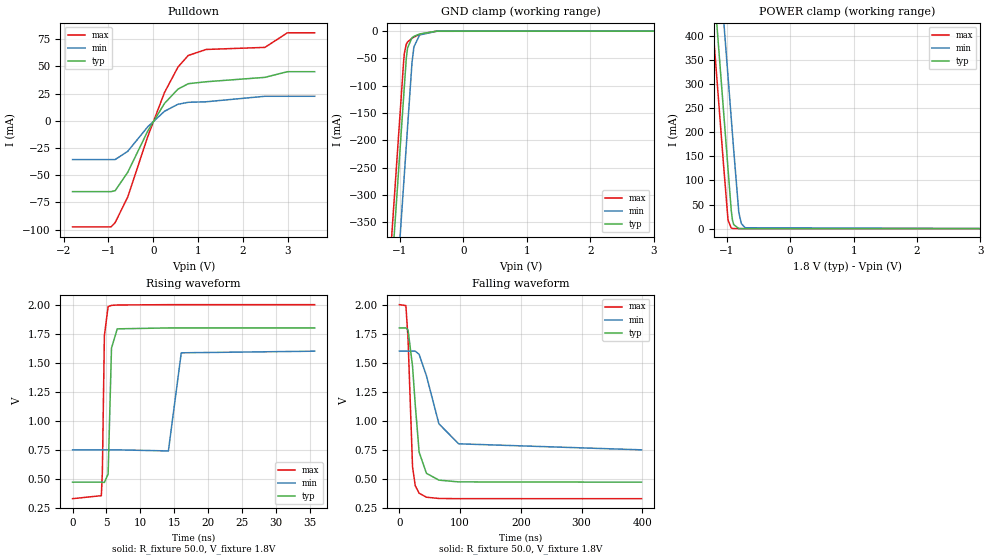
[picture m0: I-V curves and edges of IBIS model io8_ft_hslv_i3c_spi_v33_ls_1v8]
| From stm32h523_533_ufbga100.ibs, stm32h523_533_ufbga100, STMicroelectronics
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[Model]   io8_ft_hslv_i3c_spi_v33_ls_1v8
Model_type I/O_open_drain
Polarity   Non-Inverting
Enable   Active-Low
| CAP_THRESHOLD on pad IOFT is "UDTCAPC" :
| Rising=20.0% of vddiom   Falling=80.0% of vddiom
| C_comp min and max val. don't necessarily correlate with the min and max pvt
| but are the smallest and greatest pad capacitance found.
| var   typ   min   max
C_comp   3.69208pF  3.66970pF  3.86726pF
|C_comp_pulldown   3.69208pF  3.66970pF  3.86726pF
Vinl = 800.0mV
Vinh = 1.0V
Vmeas = 900.0mV   | Reference voltage for timing measurements
Cref  = 50.0pF   | Timing specification test load capacitance value
Rref  = 1.0MOhm   | Timing specification test load resistance value
Vref  = 990.0mV   | Timing specification test load voltage
[Model Spec]
| TIME_THRESHOLD on pin ZII2CV11 is "CMOS" :
| Rising=40.0% of vdd   Falling=60.0% of vdd
Vinl 693.80000mV 621.80000mV 774.80000mV
Vinh 1.05820V 933.20000mV 1.16320V
| variable   typ   min   max
[Temperature Range] 25.0 125.0 -40.0
| variable   typ   min   max
[Voltage Range] 1.8V 1.6V 2.0V
| variable   typ   min   max
[POWER Clamp Reference] 1.8V 1.6V 2.0V
| variable   typ   min   max
[GND Clamp Reference] 0V 0V 0V
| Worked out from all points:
|   slope of the pulldown table from 0 to 0.27 V, typ, clamps not added: 15.8 ohm
|   GND clamp passes 1 mA (typ) near -0.52 V on its own axis
|   POWER clamp passes 1 mA (typ) near -0.84 V on its own axis
|   rising waveform, R_fixture 50.0, V_fixture 1.8V: 20-80 % time 286ps typ, 466ps min, 243ps max; typ from 0.474 V to 1.8 V
|   falling waveform, R_fixture 50.0, V_fixture 1.8V: 20-80 % time 11.7ns typ, 28.5ns min, 6.6ns max; typ from 1.8 V to 0.474 V
[POWER Clamp]
-1.8V     1.518A     1.709A     1.407A
-1.23V    548.8mA    740.2mA    437.5mA
-1.16V    429.8mA    621.2mA    318.5mA
-1.05V    242.8mA    434.2mA    131.5mA
-980mV    123.8mA    315.2mA    17.95mA
-930mV    38.81mA    230.2mA    1.49mA
-910mV    17.82mA    196.2mA    550.8uA
-890mV    8.18mA     162.2mA    203.5uA
-810mV    363.5uA    33.6mA     3.797uA
-770mV    76.62uA    10.47mA    518.8nA
-710mV    7.416uA    1.822mA    26.33nA
3.6V      0A         0A         0A
[GND Clamp]
-1.8V     -1.579A    -1.74A     -1.515A
-1.24V    -627.3mA   -788.3mA   -562.7mA
-1.05V    -304.3mA   -465.3mA   -239.7mA
-940mV    -117.3mA   -278.3mA   -52.69mA
-930mV    -100.3mA   -261.3mA   -40.52mA
-900mV    -50.11mA   -210.3mA   -24.23mA
-880mV    -30.95mA   -176.3mA   -20.02mA
-810mV    -12.18mA   -57.97mA   -13.23mA
-780mV    -9.807mA   -29.1mA    -11.19mA
-690mV    -5.41mA    -7.142mA   -6.184mA
-420mV    -170.4uA   -446.1uA   -81.94uA
3.6V      5.755nA    953.2nA    228.2pA
| variable   typ   min   max
[Pullup Reference] 1.8V 1.6V 2.0V
| variable   typ   min   max
[Pulldown Reference] 0V 0V 0V
[Pulldown]
-1.8V     -65.02mA   -35.56mA   -97.42mA
-940mV    -65.02mA   -35.56mA   -97.42mA
-850mV    -64.17mA   -35.56mA   -93.49mA
-570mV    -47.32mA   -28.01mA   -70.04mA
-120mV    -9.088mA   -5.279mA   -14.07mA
250mV     16.04mA    8.832mA    26.05mA
550mV     29.17mA    15.25mA    49.41mA
780mV     34.17mA    17.07mA    60.14mA
1.18V     35.97mA    17.56mA    65.65mA
2.49V     40mA       22.62mA    67.56mA
2.99V     45.21mA    22.62mA    80.94mA
3.6V      45.21mA    22.62mA    80.94mA
[Ramp]
dV/dt_r 795.76282mV/283.06948ps 508.89047mV/465.17552ps 1.00097V/238.84657ps
dV/dt_f 795.7871mV/11.67095ns 508.95874mV/28.08898ns 1.00099V/6.47057ns
R_load = 50.0
| Removed startup time: 0s 0s 0s  .
| Removed end time: 35.75ns.
[Rising Waveform]
R_fixture   = 50.0
V_fixture   = 1.8V
V_fixture_min = 1.6V
V_fixture_max = 2.0V
0s        473.7mV    751.7mV    331.7mV
4.25ns    473.7mV    751.7mV    357.7mV
4.4ns     473.4mV    751.7mV    558.5mV
4.7ns     471mV      751.7mV    1.734V
5.25ns    543.7mV    751.7mV    1.984V
5.75ns    1.627V     751.7mV    1.994V
6.6ns     1.792V     751.7mV    1.997V
14.15ns   1.8V       742.2mV    2V
16.05ns   1.8V       1.586V     2V
35.75ns   1.8V       1.6V       2V
| Removed startup time: 0s 0s 0s  .
| Removed end time: 398.75ns.
[Falling Waveform]
R_fixture   = 50.0
V_fixture   = 1.8V
V_fixture_min = 1.6V
V_fixture_max = 2.0V
0s        1.8V       1.6V       2V
10.75ns   1.8V       1.6V       1.992V
14.25ns   1.783V     1.6V       1.71V
21.7ns    1.47V      1.6V       605.4mV
26.2ns    1.136V     1.6V       442.7mV
32.55ns   731.7mV    1.573V     378.8mV
44.6ns    550mV      1.388V     344.3mV
65.1ns    491.4mV    975.6mV    333.5mV
97.65ns   476mV      803.5mV    331.8mV
398.8ns   473.7mV    751.7mV    331.7mV
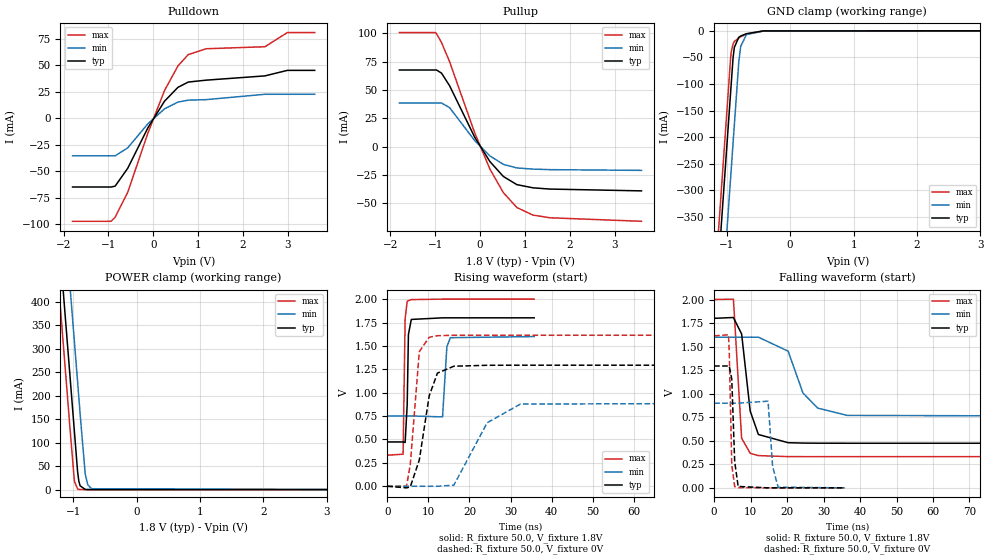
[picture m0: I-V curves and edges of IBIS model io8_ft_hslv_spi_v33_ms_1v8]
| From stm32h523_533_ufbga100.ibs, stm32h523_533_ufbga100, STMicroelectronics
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[Model]   io8_ft_hslv_spi_v33_ms_1v8
Model_type I/O
Polarity   Non-Inverting
Enable   Active-Low
| CAP_THRESHOLD on pad IOFT is "UDTCAPC" :
| Rising=20.0% of vddiom   Falling=80.0% of vddiom
| C_comp min and max val. don't necessarily correlate with the min and max pvt
| but are the smallest and greatest pad capacitance found.
| var   typ   min   max
C_comp   3.69213pF  3.66975pF  3.86731pF
|C_comp_pullup   2.29915pF  2.22620pF  2.22545pF
|C_comp_pulldown   1.39298pF  1.44355pF  1.64186pF
Vinl = 480.0mV
Vinh = 1.4V
Vmeas = 900.0mV   | Reference voltage for timing measurements
Cref  = 50.0pF   | Timing specification test load capacitance value
Rref  = 100.0MOhm   | Timing specification test load resistance value
Vref  = 900.0mV   | Timing specification test load voltage
[Model Spec]
| TIME_THRESHOLD on pin ZIV33M is "CMOS" :
| Rising=40.0% of vddiom   Falling=60.0% of vddiom
Vinl 693.80000mV 621.80000mV 774.80000mV
Vinh 1.05820V 933.20000mV 1.16320V
| variable   typ   min   max
[Temperature Range] 25.0 125.0 -40.0
| variable   typ   min   max
[Voltage Range] 1.8V 1.6V 2.0V
| variable   typ   min   max
[POWER Clamp Reference] 1.8V 1.6V 2.0V
| variable   typ   min   max
[GND Clamp Reference] 0V 0V 0V
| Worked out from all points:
|   slope of the pulldown table from 0 to 0.27 V, typ, clamps not added: 15.8 ohm
|   slope of the pullup table from 0 to 0.27 V, typ, clamps not added: 17.1 ohm
|   GND clamp passes 1 mA (typ) near -0.52 V on its own axis
|   POWER clamp passes 1 mA (typ) near -0.84 V on its own axis
|   rising waveform, R_fixture 50.0, V_fixture 1.8V: 20-80 % time 283ps typ, 446ps min, 243ps max; typ from 0.474 V to 1.8 V
|   falling waveform, R_fixture 50.0, V_fixture 1.8V: 20-80 % time 2.69ns typ, 5.8ns min, 1.28ns max; typ from 1.8 V to 0.474 V
|   rising waveform, R_fixture 50.0, V_fixture 0V: 20-80 % time 3.05ns typ, 6.53ns min, 1.58ns max; typ from 0 V to 1.29 V
|   falling waveform, R_fixture 50.0, V_fixture 0V: 20-80 % time 741ps typ, 1.07ns min, 549ps max; typ from 1.29 V to 0 V
[POWER Clamp]
-1.8V     1.518A     1.709A     1.407A
-1.23V    548.8mA    740.2mA    437.5mA
-1.16V    429.8mA    621.2mA    318.5mA
-1.05V    242.8mA    434.2mA    131.5mA
-980mV    123.8mA    315.2mA    17.95mA
-930mV    38.81mA    230.2mA    1.49mA
-910mV    17.82mA    196.2mA    550.8uA
-890mV    8.18mA     162.2mA    203.5uA
-810mV    363.5uA    33.6mA     3.797uA
-770mV    76.62uA    10.47mA    518.8nA
-710mV    7.416uA    1.822mA    26.33nA
3.6V      0A         0A         0A
[GND Clamp]
-1.8V     -1.579A    -1.74A     -1.515A
-1.24V    -627.3mA   -788.3mA   -562.7mA
-1.05V    -304.3mA   -465.3mA   -239.7mA
-940mV    -117.3mA   -278.3mA   -52.69mA
-930mV    -100.3mA   -261.3mA   -40.52mA
-900mV    -50.11mA   -210.3mA   -24.23mA
-880mV    -30.95mA   -176.3mA   -20.02mA
-810mV    -12.18mA   -57.97mA   -13.23mA
-780mV    -9.807mA   -29.1mA    -11.19mA
-690mV    -5.41mA    -7.142mA   -6.184mA
-420mV    -170.4uA   -446.1uA   -81.94uA
3.6V      5.755nA    953.2nA    228.2pA
| variable   typ   min   max
[Pullup Reference] 1.8V 1.6V 2.0V
| variable   typ   min   max
[Pulldown Reference] 0V 0V 0V
[Pullup]
-1.8V     67.74mA    38.62mA    100.8mA
-990mV    67.74mA    38.62mA    100.8mA
-970mV    67.74mA    38.62mA    99.7mA
-860mV    64.94mA    38.62mA    92.02mA
-680mV    53.84mA    34.48mA    75.07mA
-120mV    8.372mA    5.391mA    12.2mA
220mV     -13.2mA    -8.17mA    -19.85mA
520mV     -26.34mA   -15.62mA   -40.64mA
820mV     -33.51mA   -18.79mA   -53.71mA
1.18V     -36.34mA   -19.79mA   -60.45mA
1.56V     -37.44mA   -20.28mA   -62.79mA
3.6V      -39.03mA   -20.93mA   -65.9mA
[Pulldown]
-1.8V     -65.02mA   -35.56mA   -97.42mA
-940mV    -65.02mA   -35.56mA   -97.42mA
-850mV    -64.17mA   -35.56mA   -93.49mA
-570mV    -47.32mA   -28.01mA   -70.04mA
-120mV    -9.088mA   -5.279mA   -14.07mA
250mV     16.04mA    8.832mA    26.05mA
550mV     29.17mA    15.25mA    49.41mA
780mV     34.17mA    17.07mA    60.14mA
1.18V     35.97mA    17.56mA    65.65mA
2.49V     40mA       22.62mA    67.56mA
2.99V     45.21mA    22.62mA    80.94mA
3.6V      45.21mA    22.62mA    80.94mA
[Ramp]
dV/dt_r 776.16021mV/2.81986ns 539.54372mV/5.93573ns 968.53214mV/1.58093ns
dV/dt_f 795.78718mV/2.31042ns 508.97887mV/5.43453ns 1.00099V/1.27453ns
R_load = 50.0
| Removed startup time: 0s 0s 0s  .
| Removed end time: 35.75ns.
[Rising Waveform]
R_fixture   = 50.0
V_fixture   = 1.8V
V_fixture_min = 1.6V
V_fixture_max = 2.0V
0s        473.7mV    751.7mV    331.7mV
3.85ns    473.7mV    751.7mV    343.1mV
4.35ns    468mV      751.7mV    1.793V
4.85ns    872.5mV    751.7mV    1.975V
5.15ns    1.623V     751.7mV    1.984V
5.85ns    1.783V     751.7mV    1.995V
13.45ns   1.8V       741.4mV    2V
14.5ns    1.8V       1.491V     2V
15.35ns   1.8V       1.588V     2V
35.75ns   1.8V       1.6V       2V
| Removed startup time: 0s 0s 0s  .
| Removed end time: 198.75ns.
[Falling Waveform]
R_fixture   = 50.0
V_fixture   = 1.8V
V_fixture_min = 1.6V
V_fixture_max = 2.0V
0s        1.8V       1.6V       2V
5.3ns     1.809V     1.6V       2.004V
7.55ns    1.634V     1.6V       527.7mV
9.9ns     815.4mV    1.6V       366.5mV
12.15ns   566.5mV    1.6V       342.4mV
20.3ns    479.4mV    1.451V     331.9mV
24.35ns   475.4mV    1.008V     331.7mV
28.4ns    474.2mV    846.5mV    331.7mV
36.5ns    473.7mV    769.4mV    331.7mV
198.8ns   473.7mV    751.7mV    331.7mV
| Removed startup time: 0s 0s 0s  .
| Removed end time: 198.6ns.
[Rising Waveform]
R_fixture   = 50.0
V_fixture   = 0V
V_fixture_min = 0V
V_fixture_max = 0V
0s        166.5nV    437.2nV    122.3nV
4.7ns     -16.92mV   436.2nV    2.707mV
5.6ns     -6.732mV   418.8nV    234.6mV
7.8ns     281.8mV    331.7nV    1.439V
10.2ns    966mV      276.9nV    1.593V
12.2ns    1.209V     -1.233uV   1.609V
16.2ns    1.283V     11.66mV    1.614V
24.3ns    1.293V     678.8mV    1.614V
32.4ns    1.294V     878.5mV    1.614V
198.6ns   1.294V     899.2mV    1.614V
| Removed startup time: 0s 0s 0s  .
| Removed end time: 35.75ns.
[Falling Waveform]
R_fixture   = 50.0
V_fixture   = 0V
V_fixture_min = 0V
V_fixture_max = 0V
0s        1.294V     899.3mV    1.614V
3.95ns    1.294V     899.3mV    1.625V
4.15ns    1.294V     899.3mV    1.456V
4.85ns    1.155V     899.3mV    244.7mV
5.65ns    279.2mV    899.3mV    13.44mV
6.6ns     15.13mV    899.3mV    2.65mV
14.8ns    254.8uV    920.3mV    61.54uV
16.05ns   174.2uV    226.4mV    35.69uV
17.55ns   110.4uV    7.635mV    18.51uV
35.75ns   487.3nV    153.4uV    38.2nV
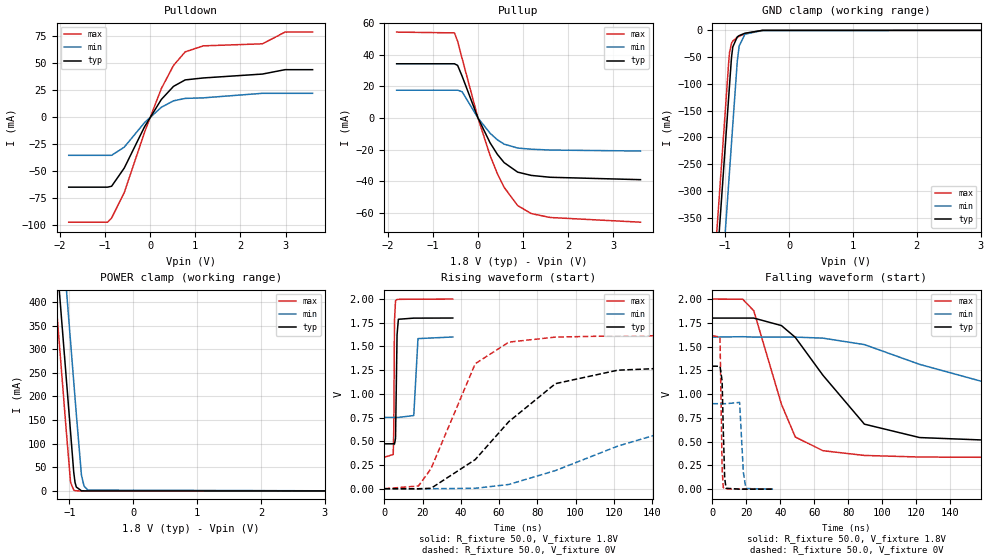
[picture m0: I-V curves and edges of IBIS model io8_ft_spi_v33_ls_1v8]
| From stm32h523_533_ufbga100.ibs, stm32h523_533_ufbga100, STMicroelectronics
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[Model]   io8_ft_spi_v33_ls_1v8
Model_type I/O
Polarity   Non-Inverting
Enable   Active-Low
| CAP_THRESHOLD on pad IOFT is "UDTCAPC" :
| Rising=20.0% of vddiom   Falling=80.0% of vddiom
| C_comp min and max val. don't necessarily correlate with the min and max pvt
| but are the smallest and greatest pad capacitance found.
| var   typ   min   max
C_comp   3.69193pF  3.66950pF  3.86716pF
|C_comp_pullup   2.28995pF  2.21765pF  2.21560pF
|C_comp_pulldown   1.40198pF  1.45185pF  1.65156pF
Vinl = 480.0mV
Vinh = 1.4V
Vmeas = 900.0mV   | Reference voltage for timing measurements
Cref  = 50.0pF   | Timing specification test load capacitance value
Rref  = 100.0MOhm   | Timing specification test load resistance value
Vref  = 900.0mV   | Timing specification test load voltage
[Model Spec]
| TIME_THRESHOLD on pin ZIV33M is "CMOS" :
| Rising=40.0% of vddiom   Falling=60.0% of vddiom
Vinl 693.80000mV 621.80000mV 774.80000mV
Vinh 1.05820V 933.20000mV 1.16320V
| variable   typ   min   max
[Temperature Range] 25.0 125.0 -40.0
| variable   typ   min   max
[Voltage Range] 1.8V 1.6V 2.0V
| variable   typ   min   max
[POWER Clamp Reference] 1.8V 1.6V 2.0V
| variable   typ   min   max
[GND Clamp Reference] 0V 0V 0V
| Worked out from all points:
|   slope of the pulldown table from 0 to 0.27 V, typ, clamps not added: 15.8 ohm
|   slope of the pullup table from 0 to 0.27 V, typ, clamps not added: 17.1 ohm
|   GND clamp passes 1 mA (typ) near -0.52 V on its own axis
|   POWER clamp passes 1 mA (typ) near -0.84 V on its own axis
|   rising waveform, R_fixture 50.0, V_fixture 1.8V: 20-80 % time 411ps typ, 846ps min, 288ps max; typ from 0.474 V to 1.8 V
|   falling waveform, R_fixture 50.0, V_fixture 1.8V: 20-80 % time 33.4ns typ, 83.1ns min, 17.2ns max; typ from 1.8 V to 0.474 V
|   rising waveform, R_fixture 50.0, V_fixture 0V: 20-80 % time 38.4ns typ, 81.5ns min, 20.1ns max; typ from 0 V to 1.29 V
|   falling waveform, R_fixture 50.0, V_fixture 0V: 20-80 % time 1.11ns typ, 1.59ns min, 753ps max; typ from 1.29 V to 0 V
[POWER Clamp]
-1.8V     1.518A     1.709A     1.407A
-1.23V    548.8mA    740.2mA    437.5mA
-1.16V    429.8mA    621.2mA    318.5mA
-1.05V    242.8mA    434.2mA    131.5mA
-980mV    123.8mA    315.2mA    17.95mA
-930mV    38.81mA    230.2mA    1.49mA
-910mV    17.82mA    196.2mA    550.8uA
-890mV    8.18mA     162.2mA    203.5uA
-810mV    363.5uA    33.6mA     3.797uA
-770mV    76.62uA    10.47mA    518.8nA
-710mV    7.416uA    1.822mA    26.34nA
3.6V      0A         0A         0A
[GND Clamp]
-1.8V     -1.579A    -1.74A     -1.515A
-1.24V    -627.3mA   -788.3mA   -562.7mA
-1.05V    -304.3mA   -465.3mA   -239.7mA
-940mV    -117.3mA   -278.3mA   -52.69mA
-930mV    -100.3mA   -261.3mA   -40.52mA
-900mV    -50.11mA   -210.3mA   -24.23mA
-880mV    -30.95mA   -176.3mA   -20.02mA
-810mV    -12.18mA   -57.97mA   -13.23mA
-780mV    -9.807mA   -29.1mA    -11.19mA
-690mV    -5.41mA    -7.142mA   -6.184mA
-420mV    -170.4uA   -446.1uA   -81.94uA
3.6V      5.755nA    953.4nA    228.2pA
| variable   typ   min   max
[Pullup Reference] 1.8V 1.6V 2.0V
| variable   typ   min   max
[Pulldown Reference] 0V 0V 0V
[Pullup]
-1.8V     34.19mA    17.51mA    54.21mA
-520mV    34.19mA    17.51mA    53.7mA
-450mV    33.18mA    17.51mA    48.44mA
-350mV    26.34mA    16.51mA    37.53mA
0V        7.5pA      697pA      4.403pA
270mV     -15.79mA   -9.711mA   -23.84mA
430mV     -23.01mA   -13.84mA   -35.21mA
580mV     -28.25mA   -16.58mA   -43.88mA
880mV     -34.28mA   -19.05mA   -55.41mA
1.18V     -36.34mA   -19.79mA   -60.45mA
1.6V      -37.52mA   -20.32mA   -62.94mA
3.6V      -39.03mA   -20.93mA   -65.9mA
[Pulldown]
-1.8V     -65.02mA   -35.56mA   -97.42mA
-940mV    -65.02mA   -35.56mA   -97.42mA
-850mV    -64.17mA   -35.56mA   -93.49mA
-570mV    -47.32mA   -28.01mA   -70.04mA
-120mV    -9.088mA   -5.279mA   -14.07mA
250mV     16.04mA    8.831mA    26.05mA
520mV     28.19mA    14.82mA    47.53mA
780mV     34.17mA    17.07mA    60.14mA
1.18V     35.97mA    17.56mA    65.65mA
2.49V     39.57mA    21.77mA    67.55mA
2.99V     43.62mA    21.77mA    78.38mA
3.6V      43.62mA    21.77mA    78.38mA
[Ramp]
dV/dt_r 776.12017mV/37.99286ns 538.49733mV/81.32904ns 968.53764mV/19.74907ns
dV/dt_f 795.72738mV/32.65549ns 503.38074mV/83.00234ns 1.00099V/15.7969ns
R_load = 50.0
| Removed startup time: 0s 0s 0s  .
| Removed end time: 35.75ns.
[Rising Waveform]
R_fixture   = 50.0
V_fixture   = 1.8V
V_fixture_min = 1.6V
V_fixture_max = 2.0V
0s        473.7mV    751.8mV    331.7mV
4.6ns     473.7mV    751.8mV    361.1mV
4.9ns     472.4mV    751.8mV    639.4mV
5.25ns    470.4mV    751.8mV    1.768V
5.8ns     530.2mV    751.8mV    1.983V
6.6ns     1.624V     751.8mV    1.995V
7.3ns     1.787V     751.8mV    1.997V
15.35ns   1.799V     771.8mV    1.999V
17.55ns   1.799V     1.583V     1.999V
35.75ns   1.8V       1.6V       2V
| Removed startup time: 0s 0s 0s  .
| Removed end time: 398.75ns.
[Falling Waveform]
R_fixture   = 50.0
V_fixture   = 1.8V
V_fixture_min = 1.6V
V_fixture_max = 2.0V
0s        1.8V       1.6V       2V
17.85ns   1.8V       1.604V     1.999V
24.4ns    1.8V       1.6V       1.877V
40.7ns    1.721V     1.6V       892.7mV
48.85ns   1.597V     1.6V       549mV
65.1ns    1.199V     1.589V     404.9mV
89.55ns   684mV      1.521V     355mV
122.1ns   543mV      1.313V     338.2mV
211.6ns   481.2mV    874.7mV    331.9mV
398.8ns   473.8mV    761mV      331.7mV
| Removed startup time: 0s 0s 0s  .
| Removed end time: 398.6ns.
[Rising Waveform]
R_fixture   = 50.0
V_fixture   = 0V
V_fixture_min = 0V
V_fixture_max = 0V
0s        179.1nV    440.8nV    129.9nV
17.8ns    -196.8uV   -4.768mV   28.85mV
24.4ns    4.63mV     -125.2uV   212.3mV
47.5ns    307mV      4.284mV    1.318V
65.1ns    707.6mV    44.81mV    1.546V
89.5ns    1.108V     191.4mV    1.599V
122.1ns   1.25V      449.3mV    1.612V
162.7ns   1.284V     691.1mV    1.614V
211.6ns   1.292V     827.8mV    1.614V
398.6ns   1.294V     897.5mV    1.614V
| Removed startup time: 0s 0s 0s  .
| Removed end time: 35.75ns.
[Falling Waveform]
R_fixture   = 50.0
V_fixture   = 0V
V_fixture_min = 0V
V_fixture_max = 0V
0s        1.294V     899.3mV    1.614V
4.5ns     1.293V     899.3mV    1.601V
5.75ns    1.138V     899.3mV    223.4mV
6.4ns     649.1mV    899.3mV    19.54mV
7.25ns    120.7mV    899.3mV    3.099mV
8.05ns    9.808mV    899.3mV    1.828mV
16.05ns   383.2uV    912.9mV    591.9uV
18.25ns   327.7uV    177.6mV    571.1uV
19.75ns   306.3uV    7.021mV    578.9uV
35.75ns   369.2uV    161.8uV    238.3uV
